VERSION 5.7 ;
  NOWIREEXTENSIONATPIN ON ;
  DIVIDERCHAR "/" ;
  BUSBITCHARS "[]" ;
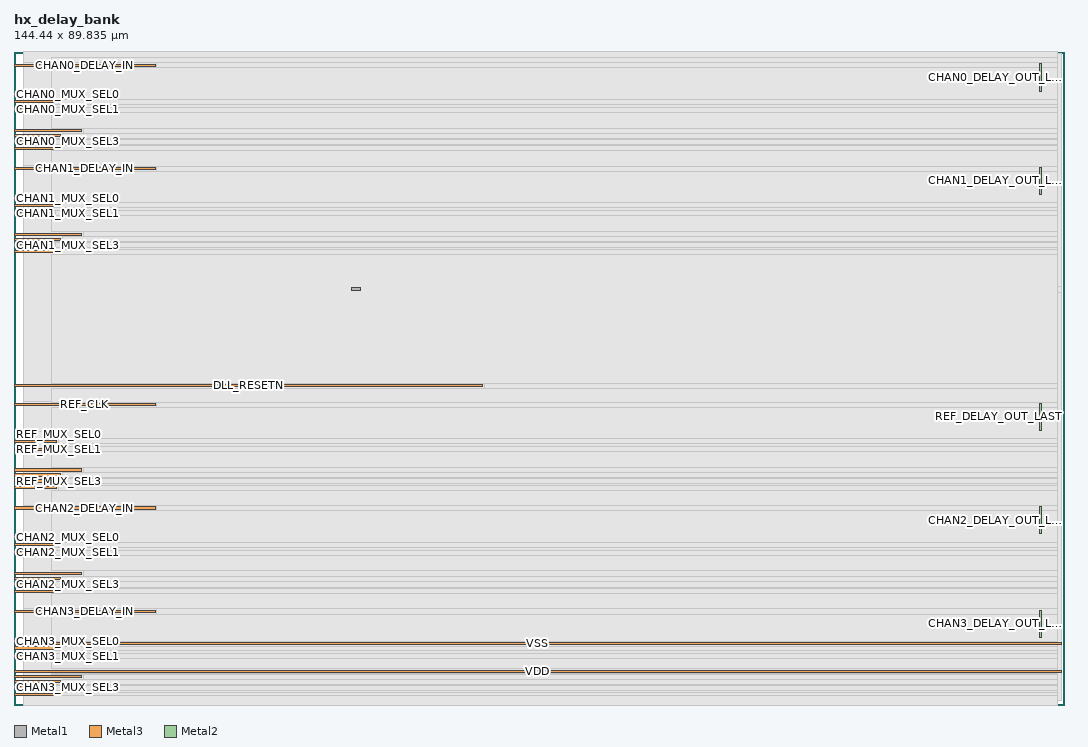
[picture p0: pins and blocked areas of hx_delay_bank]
MACRO hx_delay_bank
  CLASS BLOCK ;
  FOREIGN hx_delay_bank ;
  ORIGIN 0.000 0.000 ;
  SIZE 144.440 BY 89.835 ;
  PIN VDD
    DIRECTION INPUT ;
    USE POWER ;
    PORT
      LAYER Metal1 ;
        RECT 46.455 56.965 47.620 57.405 ;
    END
    PORT
      LAYER Metal3 ;
        RECT 0.000 4.490 144.150 4.780 ;
    END
  END VDD
  PIN CHAN0_DELAY_OUT_LAST
    DIRECTION OUTPUT ;
    ANTENNADIFFAREA 0.632400 ;
    PORT
      LAYER Metal2 ;
        RECT 141.010 84.450 141.300 88.190 ;
    END
  END CHAN0_DELAY_OUT_LAST
  PIN CHAN1_DELAY_OUT_LAST
    DIRECTION OUTPUT ;
    ANTENNADIFFAREA 0.632400 ;
    PORT
      LAYER Metal2 ;
        RECT 141.010 70.225 141.300 73.965 ;
    END
  END CHAN1_DELAY_OUT_LAST
  PIN CHAN3_DELAY_OUT_LAST
    DIRECTION OUTPUT ;
    ANTENNADIFFAREA 0.632400 ;
    PORT
      LAYER Metal2 ;
        RECT 141.010 9.315 141.300 13.055 ;
    END
  END CHAN3_DELAY_OUT_LAST
  PIN CHAN2_DELAY_OUT_LAST
    DIRECTION OUTPUT ;
    ANTENNADIFFAREA 0.632400 ;
    PORT
      LAYER Metal2 ;
        RECT 141.010 23.540 141.300 27.280 ;
    END
  END CHAN2_DELAY_OUT_LAST
  PIN REF_DELAY_OUT_LAST
    DIRECTION OUTPUT ;
    ANTENNAGATEAREA 0.241800 ;
    ANTENNADIFFAREA 0.632400 ;
    PORT
      LAYER Metal2 ;
        RECT 141.010 37.765 141.300 41.505 ;
    END
  END REF_DELAY_OUT_LAST
  PIN DLL_RESETN
    DIRECTION INPUT ;
    ANTENNAGATEAREA 0.729400 ;
    PORT
      LAYER Metal3 ;
        RECT 0.000 43.745 64.485 44.035 ;
    END
  END DLL_RESETN
  PIN REF_CLK
    DIRECTION INPUT ;
    ANTENNAGATEAREA 1.097400 ;
    PORT
      LAYER Metal3 ;
        RECT 0.000 41.175 19.455 41.465 ;
    END
  END REF_CLK
  PIN VSS
    DIRECTION INPUT ;
    USE GROUND ;
    PORT
      LAYER Metal3 ;
        RECT 0.000 8.270 144.150 8.560 ;
    END
  END VSS
  PIN CHAN0_DELAY_IN
    DIRECTION INPUT ;
    ANTENNAGATEAREA 0.613800 ;
    PORT
      LAYER Metal3 ;
        RECT 0.000 87.860 19.455 88.150 ;
    END
  END CHAN0_DELAY_IN
  PIN CHAN0_MUX_SEL0
    DIRECTION INPUT ;
    ANTENNAGATEAREA 0.626600 ;
    PORT
      LAYER Metal3 ;
        RECT 0.000 82.830 5.875 83.120 ;
    END
  END CHAN0_MUX_SEL0
  PIN CHAN0_MUX_SEL1
    DIRECTION INPUT ;
    ANTENNAGATEAREA 0.626600 ;
    PORT
      LAYER Metal3 ;
        RECT 0.000 81.720 5.500 82.010 ;
    END
  END CHAN0_MUX_SEL1
  PIN CHAN0_MUX_OUT
    DIRECTION OUTPUT ;
    ANTENNADIFFAREA 0.706800 ;
    PORT
      LAYER Metal3 ;
        RECT 0.000 78.860 9.315 79.150 ;
    END
  END CHAN0_MUX_OUT
  PIN CHAN0_MUX_SEL4
    DIRECTION INPUT ;
    ANTENNAGATEAREA 0.483600 ;
    PORT
      LAYER Metal3 ;
        RECT 0.000 78.175 6.425 78.465 ;
    END
  END CHAN0_MUX_SEL4
  PIN CHAN0_MUX_SEL2
    DIRECTION INPUT ;
    ANTENNAGATEAREA 0.626600 ;
    PORT
      LAYER Metal3 ;
        RECT 0.000 76.420 5.875 76.710 ;
    END
  END CHAN0_MUX_SEL2
  PIN CHAN0_MUX_SEL3
    DIRECTION INPUT ;
    ANTENNAGATEAREA 0.626600 ;
    PORT
      LAYER Metal3 ;
        RECT 0.000 77.350 5.500 77.640 ;
    END
  END CHAN0_MUX_SEL3
  PIN CHAN1_DELAY_IN
    DIRECTION INPUT ;
    ANTENNAGATEAREA 0.613800 ;
    PORT
      LAYER Metal3 ;
        RECT 0.000 73.635 19.455 73.925 ;
    END
  END CHAN1_DELAY_IN
  PIN CHAN1_MUX_SEL0
    DIRECTION INPUT ;
    ANTENNAGATEAREA 0.626600 ;
    PORT
      LAYER Metal3 ;
        RECT 0.000 68.605 5.875 68.895 ;
    END
  END CHAN1_MUX_SEL0
  PIN CHAN1_MUX_SEL1
    DIRECTION INPUT ;
    ANTENNAGATEAREA 0.626600 ;
    PORT
      LAYER Metal3 ;
        RECT 0.000 67.495 5.500 67.785 ;
    END
  END CHAN1_MUX_SEL1
  PIN CHAN1_MUX_OUT
    DIRECTION OUTPUT ;
    ANTENNADIFFAREA 0.706800 ;
    PORT
      LAYER Metal3 ;
        RECT 0.000 64.635 9.315 64.925 ;
    END
  END CHAN1_MUX_OUT
  PIN CHAN1_MUX_SEL4
    DIRECTION INPUT ;
    ANTENNAGATEAREA 0.483600 ;
    PORT
      LAYER Metal3 ;
        RECT 0.000 63.950 6.425 64.240 ;
    END
  END CHAN1_MUX_SEL4
  PIN CHAN1_MUX_SEL2
    DIRECTION INPUT ;
    ANTENNAGATEAREA 0.626600 ;
    PORT
      LAYER Metal3 ;
        RECT 0.000 62.195 5.875 62.485 ;
    END
  END CHAN1_MUX_SEL2
  PIN CHAN1_MUX_SEL3
    DIRECTION INPUT ;
    ANTENNAGATEAREA 0.626600 ;
    PORT
      LAYER Metal3 ;
        RECT 0.000 63.125 5.500 63.415 ;
    END
  END CHAN1_MUX_SEL3
  PIN CHAN3_DELAY_IN
    DIRECTION INPUT ;
    ANTENNAGATEAREA 0.613800 ;
    PORT
      LAYER Metal3 ;
        RECT 0.000 12.725 19.455 13.015 ;
    END
  END CHAN3_DELAY_IN
  PIN CHAN2_DELAY_IN
    DIRECTION INPUT ;
    ANTENNAGATEAREA 0.613800 ;
    PORT
      LAYER Metal3 ;
        RECT 0.000 26.950 19.455 27.240 ;
    END
  END CHAN2_DELAY_IN
  PIN CHAN3_MUX_SEL0
    DIRECTION INPUT ;
    ANTENNAGATEAREA 0.626600 ;
    PORT
      LAYER Metal3 ;
        RECT 0.000 7.695 5.875 7.985 ;
    END
  END CHAN3_MUX_SEL0
  PIN CHAN2_MUX_SEL0
    DIRECTION INPUT ;
    ANTENNAGATEAREA 0.626600 ;
    PORT
      LAYER Metal3 ;
        RECT 0.000 21.920 5.875 22.210 ;
    END
  END CHAN2_MUX_SEL0
  PIN CHAN3_MUX_SEL1
    DIRECTION INPUT ;
    ANTENNAGATEAREA 0.626600 ;
    PORT
      LAYER Metal3 ;
        RECT 0.000 6.585 5.500 6.875 ;
    END
  END CHAN3_MUX_SEL1
  PIN CHAN2_MUX_SEL1
    DIRECTION INPUT ;
    ANTENNAGATEAREA 0.626600 ;
    PORT
      LAYER Metal3 ;
        RECT 0.000 20.810 5.500 21.100 ;
    END
  END CHAN2_MUX_SEL1
  PIN CHAN3_MUX_OUT
    DIRECTION OUTPUT ;
    ANTENNADIFFAREA 0.706800 ;
    PORT
      LAYER Metal3 ;
        RECT 0.000 3.725 9.315 4.015 ;
    END
  END CHAN3_MUX_OUT
  PIN CHAN2_MUX_OUT
    DIRECTION OUTPUT ;
    ANTENNADIFFAREA 0.706800 ;
    PORT
      LAYER Metal3 ;
        RECT 0.000 17.950 9.315 18.240 ;
    END
  END CHAN2_MUX_OUT
  PIN CHAN3_MUX_SEL4
    DIRECTION INPUT ;
    ANTENNAGATEAREA 0.483600 ;
    PORT
      LAYER Metal3 ;
        RECT 0.000 3.040 6.425 3.330 ;
    END
  END CHAN3_MUX_SEL4
  PIN CHAN2_MUX_SEL4
    DIRECTION INPUT ;
    ANTENNAGATEAREA 0.483600 ;
    PORT
      LAYER Metal3 ;
        RECT 0.000 17.265 6.425 17.555 ;
    END
  END CHAN2_MUX_SEL4
  PIN CHAN3_MUX_SEL2
    DIRECTION INPUT ;
    ANTENNAGATEAREA 0.626600 ;
    PORT
      LAYER Metal3 ;
        RECT 0.000 1.285 5.875 1.575 ;
    END
  END CHAN3_MUX_SEL2
  PIN CHAN2_MUX_SEL2
    DIRECTION INPUT ;
    ANTENNAGATEAREA 0.626600 ;
    PORT
      LAYER Metal3 ;
        RECT 0.000 15.510 5.875 15.800 ;
    END
  END CHAN2_MUX_SEL2
  PIN CHAN3_MUX_SEL3
    DIRECTION INPUT ;
    ANTENNAGATEAREA 0.626600 ;
    PORT
      LAYER Metal3 ;
        RECT 0.000 2.215 5.500 2.505 ;
    END
  END CHAN3_MUX_SEL3
  PIN CHAN2_MUX_SEL3
    DIRECTION INPUT ;
    ANTENNAGATEAREA 0.626600 ;
    PORT
      LAYER Metal3 ;
        RECT 0.000 16.440 5.500 16.730 ;
    END
  END CHAN2_MUX_SEL3
  PIN REF_MUX_SEL0
    DIRECTION INPUT ;
    ANTENNAGATEAREA 0.626600 ;
    PORT
      LAYER Metal3 ;
        RECT 0.000 36.145 5.875 36.435 ;
    END
  END REF_MUX_SEL0
  PIN REF_MUX_SEL1
    DIRECTION INPUT ;
    ANTENNAGATEAREA 0.626600 ;
    PORT
      LAYER Metal3 ;
        RECT 0.000 35.035 5.500 35.325 ;
    END
  END REF_MUX_SEL1
  PIN REF_MUX_OUT
    DIRECTION OUTPUT ;
    ANTENNADIFFAREA 0.706800 ;
    PORT
      LAYER Metal3 ;
        RECT 0.000 32.175 9.315 32.465 ;
    END
  END REF_MUX_OUT
  PIN REF_MUX_SEL4
    DIRECTION INPUT ;
    ANTENNAGATEAREA 0.483600 ;
    PORT
      LAYER Metal3 ;
        RECT 0.000 31.490 6.425 31.780 ;
    END
  END REF_MUX_SEL4
  PIN REF_MUX_SEL2
    DIRECTION INPUT ;
    ANTENNAGATEAREA 0.626600 ;
    PORT
      LAYER Metal3 ;
        RECT 0.000 29.735 5.875 30.025 ;
    END
  END REF_MUX_SEL2
  PIN REF_MUX_SEL3
    DIRECTION INPUT ;
    ANTENNAGATEAREA 0.626600 ;
    PORT
      LAYER Metal3 ;
        RECT 0.000 30.665 5.500 30.955 ;
    END
  END REF_MUX_SEL3
  OBS
      LAYER GatPoly ;
        RECT 5.500 0.705 144.085 89.565 ;
      LAYER Metal1 ;
        RECT 1.300 57.585 144.155 89.635 ;
        RECT 1.300 56.785 46.275 57.585 ;
        RECT 47.800 56.785 144.155 57.585 ;
        RECT 1.300 0.635 144.155 56.785 ;
      LAYER Metal2 ;
        RECT 1.300 88.400 143.595 89.835 ;
        RECT 1.300 84.240 140.800 88.400 ;
        RECT 141.510 84.240 143.595 88.400 ;
        RECT 1.300 74.175 143.595 84.240 ;
        RECT 1.300 70.015 140.800 74.175 ;
        RECT 141.510 70.015 143.595 74.175 ;
        RECT 1.300 41.715 143.595 70.015 ;
        RECT 1.300 37.555 140.800 41.715 ;
        RECT 141.510 37.555 143.595 41.715 ;
        RECT 1.300 27.490 143.595 37.555 ;
        RECT 1.300 23.330 140.800 27.490 ;
        RECT 141.510 23.330 143.595 27.490 ;
        RECT 1.300 13.265 143.595 23.330 ;
        RECT 1.300 9.105 140.800 13.265 ;
        RECT 141.510 9.105 143.595 13.265 ;
        RECT 1.300 0.000 143.595 9.105 ;
      LAYER Metal3 ;
        RECT 5.210 88.360 143.595 89.015 ;
        RECT 19.665 87.650 143.595 88.360 ;
        RECT 5.210 83.330 143.595 87.650 ;
        RECT 6.085 82.620 143.595 83.330 ;
        RECT 5.210 82.220 143.595 82.620 ;
        RECT 5.710 81.510 143.595 82.220 ;
        RECT 5.210 79.360 143.595 81.510 ;
        RECT 9.525 78.650 143.595 79.360 ;
        RECT 6.635 77.965 143.595 78.650 ;
        RECT 5.210 77.850 143.595 77.965 ;
        RECT 5.710 77.140 143.595 77.850 ;
        RECT 5.210 76.920 143.595 77.140 ;
        RECT 6.085 76.210 143.595 76.920 ;
        RECT 5.210 74.135 143.595 76.210 ;
        RECT 19.665 73.425 143.595 74.135 ;
        RECT 5.210 69.105 143.595 73.425 ;
        RECT 6.085 68.395 143.595 69.105 ;
        RECT 5.210 67.995 143.595 68.395 ;
        RECT 5.710 67.285 143.595 67.995 ;
        RECT 5.210 65.135 143.595 67.285 ;
        RECT 9.525 64.425 143.595 65.135 ;
        RECT 6.635 63.740 143.595 64.425 ;
        RECT 5.210 63.625 143.595 63.740 ;
        RECT 5.710 62.915 143.595 63.625 ;
        RECT 5.210 62.695 143.595 62.915 ;
        RECT 6.085 61.985 143.595 62.695 ;
        RECT 5.210 44.245 143.595 61.985 ;
        RECT 64.695 43.535 143.595 44.245 ;
        RECT 5.210 41.675 143.595 43.535 ;
        RECT 19.665 40.965 143.595 41.675 ;
        RECT 5.210 36.645 143.595 40.965 ;
        RECT 6.085 35.935 143.595 36.645 ;
        RECT 5.210 35.535 143.595 35.935 ;
        RECT 5.710 34.825 143.595 35.535 ;
        RECT 5.210 32.675 143.595 34.825 ;
        RECT 9.525 31.965 143.595 32.675 ;
        RECT 6.635 31.280 143.595 31.965 ;
        RECT 5.210 31.165 143.595 31.280 ;
        RECT 5.710 30.455 143.595 31.165 ;
        RECT 5.210 30.235 143.595 30.455 ;
        RECT 6.085 29.525 143.595 30.235 ;
        RECT 5.210 27.450 143.595 29.525 ;
        RECT 19.665 26.740 143.595 27.450 ;
        RECT 5.210 22.420 143.595 26.740 ;
        RECT 6.085 21.710 143.595 22.420 ;
        RECT 5.210 21.310 143.595 21.710 ;
        RECT 5.710 20.600 143.595 21.310 ;
        RECT 5.210 18.450 143.595 20.600 ;
        RECT 9.525 17.740 143.595 18.450 ;
        RECT 6.635 17.055 143.595 17.740 ;
        RECT 5.210 16.940 143.595 17.055 ;
        RECT 5.710 16.230 143.595 16.940 ;
        RECT 5.210 16.010 143.595 16.230 ;
        RECT 6.085 15.300 143.595 16.010 ;
        RECT 5.210 13.225 143.595 15.300 ;
        RECT 19.665 12.515 143.595 13.225 ;
        RECT 5.210 8.770 143.595 12.515 ;
        RECT 6.085 7.485 143.595 8.060 ;
        RECT 5.210 7.085 143.595 7.485 ;
        RECT 5.710 6.375 143.595 7.085 ;
        RECT 5.210 4.990 143.595 6.375 ;
        RECT 5.210 4.225 143.595 4.280 ;
        RECT 9.525 3.515 143.595 4.225 ;
        RECT 6.635 2.830 143.595 3.515 ;
        RECT 5.210 2.715 143.595 2.830 ;
        RECT 5.710 2.005 143.595 2.715 ;
        RECT 5.210 1.785 143.595 2.005 ;
        RECT 6.085 1.285 143.595 1.785 ;
  END
END hx_delay_bank
END LIBRARY

